VERSION 5.8 ;
BUSBITCHARS "[]" ;
DIVIDERCHAR "/" ;

PROPERTYDEFINITIONS
  PIN LEF58_MUSTJOINALLPORTS STRING ;
END PROPERTYDEFINITIONS

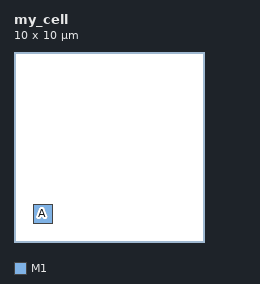
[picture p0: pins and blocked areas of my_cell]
MACRO my_cell
  CLASS CORE ;
  SIZE 10 BY 10 ;
  PIN A
    DIRECTION INPUT ;
    USE SIGNAL ;
    PROPERTY LEF58_MUSTJOINALLPORTS "MUSTJOINALLPORTS ; " ;
    PORT
      LAYER M1 ;
      RECT 1 1 2 2 ;
    END
  END A
END my_cell
